VERSION 5.7 ;
  NOWIREEXTENSIONATPIN ON ;
  DIVIDERCHAR "/" ;
  BUSBITCHARS "[]" ;
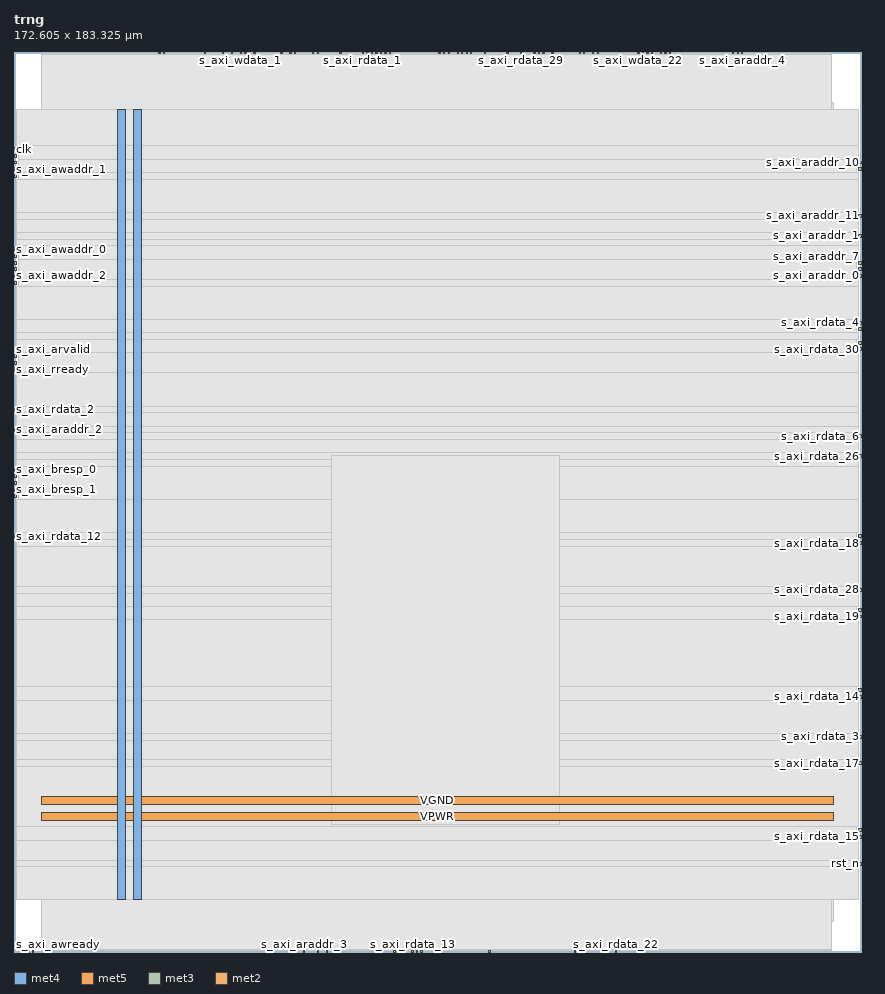
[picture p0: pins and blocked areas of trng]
MACRO trng
  CLASS BLOCK ;
  FOREIGN trng ;
  ORIGIN 0.000 0.000 ;
  SIZE 172.605 BY 183.325 ;
  PIN VGND
    DIRECTION INOUT ;
    USE GROUND ;
    PORT
      LAYER met4 ;
        RECT 24.340 10.640 25.940 171.600 ;
    END
    PORT
      LAYER met5 ;
        RECT 5.520 30.030 166.980 31.630 ;
    END
  END VGND
  PIN VPWR
    DIRECTION INOUT ;
    USE POWER ;
    PORT
      LAYER met4 ;
        RECT 21.040 10.640 22.640 171.600 ;
    END
    PORT
      LAYER met5 ;
        RECT 5.520 26.730 166.980 28.330 ;
    END
  END VPWR
  PIN clk
    DIRECTION INPUT ;
    USE SIGNAL ;
    ANTENNAGATEAREA 1.286700 ;
    ANTENNADIFFAREA 0.434700 ;
    PORT
      LAYER met3 ;
        RECT 0.000 163.240 0.600 163.840 ;
    END
  END clk
  PIN irq
    DIRECTION OUTPUT ;
    USE SIGNAL ;
    ANTENNAGATEAREA 0.434700 ;
    ANTENNADIFFAREA 1.137600 ;
    PORT
      LAYER met2 ;
        RECT 73.690 183.045 73.970 183.325 ;
    END
  END irq
  PIN rst_n
    DIRECTION INPUT ;
    USE SIGNAL ;
    ANTENNAGATEAREA 0.647700 ;
    ANTENNADIFFAREA 0.434700 ;
    PORT
      LAYER met3 ;
        RECT 172.005 17.720 172.605 18.320 ;
    END
  END rst_n
  PIN s_axi_araddr_0
    DIRECTION INPUT ;
    USE SIGNAL ;
    ANTENNAGATEAREA 0.647700 ;
    ANTENNADIFFAREA 0.434700 ;
    PORT
      LAYER met3 ;
        RECT 172.005 137.400 172.605 138.000 ;
    END
  END s_axi_araddr_0
  PIN s_axi_araddr_1
    DIRECTION INPUT ;
    USE SIGNAL ;
    ANTENNAGATEAREA 0.647700 ;
    ANTENNADIFFAREA 0.434700 ;
    PORT
      LAYER met3 ;
        RECT 172.005 145.560 172.605 146.160 ;
    END
  END s_axi_araddr_1
  PIN s_axi_araddr_10
    DIRECTION INPUT ;
    USE SIGNAL ;
    ANTENNAGATEAREA 0.647700 ;
    ANTENNADIFFAREA 0.434700 ;
    PORT
      LAYER met3 ;
        RECT 172.005 160.520 172.605 161.120 ;
    END
  END s_axi_araddr_10
  PIN s_axi_araddr_11
    DIRECTION INPUT ;
    USE SIGNAL ;
    ANTENNAGATEAREA 0.647700 ;
    ANTENNADIFFAREA 0.434700 ;
    PORT
      LAYER met3 ;
        RECT 172.005 149.640 172.605 150.240 ;
    END
  END s_axi_araddr_11
  PIN s_axi_araddr_2
    DIRECTION INPUT ;
    USE SIGNAL ;
    ANTENNAGATEAREA 0.647700 ;
    ANTENNADIFFAREA 0.434700 ;
    PORT
      LAYER met3 ;
        RECT 0.000 106.120 0.600 106.720 ;
    END
  END s_axi_araddr_2
  PIN s_axi_araddr_3
    DIRECTION INPUT ;
    USE SIGNAL ;
    ANTENNAGATEAREA 0.647700 ;
    ANTENNADIFFAREA 0.434700 ;
    PORT
      LAYER met2 ;
        RECT 58.970 0.000 59.250 0.280 ;
    END
  END s_axi_araddr_3
  PIN s_axi_araddr_4
    DIRECTION INPUT ;
    USE SIGNAL ;
    ANTENNAGATEAREA 0.647700 ;
    ANTENNADIFFAREA 0.434700 ;
    PORT
      LAYER met2 ;
        RECT 148.210 183.045 148.490 183.325 ;
    END
  END s_axi_araddr_4
  PIN s_axi_araddr_5
    DIRECTION INPUT ;
    USE SIGNAL ;
    ANTENNAGATEAREA 0.647700 ;
    ANTENNADIFFAREA 0.434700 ;
    PORT
      LAYER met3 ;
        RECT 172.005 138.760 172.605 139.360 ;
    END
  END s_axi_araddr_5
  PIN s_axi_araddr_6
    DIRECTION INPUT ;
    USE SIGNAL ;
    ANTENNAGATEAREA 0.647700 ;
    ANTENNADIFFAREA 0.434700 ;
    PORT
      LAYER met2 ;
        RECT 147.290 183.045 147.570 183.325 ;
    END
  END s_axi_araddr_6
  PIN s_axi_araddr_7
    DIRECTION INPUT ;
    USE SIGNAL ;
    ANTENNAGATEAREA 0.647700 ;
    ANTENNADIFFAREA 0.434700 ;
    PORT
      LAYER met3 ;
        RECT 172.005 140.120 172.605 140.720 ;
    END
  END s_axi_araddr_7
  PIN s_axi_araddr_8
    DIRECTION INPUT ;
    USE SIGNAL ;
    ANTENNAGATEAREA 0.647700 ;
    ANTENNADIFFAREA 0.434700 ;
    PORT
      LAYER met2 ;
        RECT 146.370 183.045 146.650 183.325 ;
    END
  END s_axi_araddr_8
  PIN s_axi_araddr_9
    DIRECTION INPUT ;
    USE SIGNAL ;
    ANTENNAGATEAREA 0.647700 ;
    ANTENNADIFFAREA 0.434700 ;
    PORT
      LAYER met3 ;
        RECT 172.005 159.160 172.605 159.760 ;
    END
  END s_axi_araddr_9
  PIN s_axi_arready
    DIRECTION OUTPUT ;
    USE SIGNAL ;
    PORT
      LAYER met2 ;
        RECT 1.930 0.000 2.210 0.280 ;
    END
  END s_axi_arready
  PIN s_axi_arvalid
    DIRECTION INPUT ;
    USE SIGNAL ;
    ANTENNAGATEAREA 0.647700 ;
    ANTENNADIFFAREA 0.434700 ;
    PORT
      LAYER met3 ;
        RECT 0.000 121.080 0.600 121.680 ;
    END
  END s_axi_arvalid
  PIN s_axi_awaddr_0
    DIRECTION INPUT ;
    USE SIGNAL ;
    ANTENNAGATEAREA 0.647700 ;
    ANTENNADIFFAREA 0.434700 ;
    PORT
      LAYER met3 ;
        RECT 0.000 142.840 0.600 143.440 ;
    END
  END s_axi_awaddr_0
  PIN s_axi_awaddr_1
    DIRECTION INPUT ;
    USE SIGNAL ;
    ANTENNAGATEAREA 0.647700 ;
    ANTENNADIFFAREA 0.434700 ;
    PORT
      LAYER met3 ;
        RECT 0.000 159.160 0.600 159.760 ;
    END
  END s_axi_awaddr_1
  PIN s_axi_awaddr_10
    DIRECTION INPUT ;
    USE SIGNAL ;
    ANTENNAGATEAREA 0.647700 ;
    ANTENNADIFFAREA 0.434700 ;
    PORT
      LAYER met2 ;
        RECT 29.530 183.045 29.810 183.325 ;
    END
  END s_axi_awaddr_10
  PIN s_axi_awaddr_11
    DIRECTION INPUT ;
    USE SIGNAL ;
    ANTENNAGATEAREA 0.647700 ;
    ANTENNADIFFAREA 0.434700 ;
    PORT
      LAYER met3 ;
        RECT 0.000 160.520 0.600 161.120 ;
    END
  END s_axi_awaddr_11
  PIN s_axi_awaddr_2
    DIRECTION INPUT ;
    USE SIGNAL ;
    ANTENNAGATEAREA 0.647700 ;
    ANTENNADIFFAREA 0.434700 ;
    PORT
      LAYER met3 ;
        RECT 0.000 137.400 0.600 138.000 ;
    END
  END s_axi_awaddr_2
  PIN s_axi_awaddr_3
    DIRECTION INPUT ;
    USE SIGNAL ;
    ANTENNAGATEAREA 0.647700 ;
    ANTENNADIFFAREA 0.434700 ;
    PORT
      LAYER met3 ;
        RECT 0.000 138.760 0.600 139.360 ;
    END
  END s_axi_awaddr_3
  PIN s_axi_awaddr_4
    DIRECTION INPUT ;
    USE SIGNAL ;
    ANTENNAGATEAREA 0.647700 ;
    ANTENNADIFFAREA 0.434700 ;
    PORT
      LAYER met3 ;
        RECT 0.000 140.120 0.600 140.720 ;
    END
  END s_axi_awaddr_4
  PIN s_axi_awaddr_5
    DIRECTION INPUT ;
    USE SIGNAL ;
    ANTENNAGATEAREA 0.647700 ;
    ANTENNADIFFAREA 0.434700 ;
    PORT
      LAYER met3 ;
        RECT 0.000 136.040 0.600 136.640 ;
    END
  END s_axi_awaddr_5
  PIN s_axi_awaddr_6
    DIRECTION INPUT ;
    USE SIGNAL ;
    ANTENNAGATEAREA 0.647700 ;
    ANTENNADIFFAREA 0.434700 ;
    PORT
      LAYER met3 ;
        RECT 0.000 157.800 0.600 158.400 ;
    END
  END s_axi_awaddr_6
  PIN s_axi_awaddr_7
    DIRECTION INPUT ;
    USE SIGNAL ;
    ANTENNAGATEAREA 0.647700 ;
    ANTENNADIFFAREA 0.434700 ;
    PORT
      LAYER met3 ;
        RECT 0.000 161.880 0.600 162.480 ;
    END
  END s_axi_awaddr_7
  PIN s_axi_awaddr_8
    DIRECTION INPUT ;
    USE SIGNAL ;
    ANTENNAGATEAREA 0.647700 ;
    ANTENNADIFFAREA 0.434700 ;
    PORT
      LAYER met2 ;
        RECT 30.450 183.045 30.730 183.325 ;
    END
  END s_axi_awaddr_8
  PIN s_axi_awaddr_9
    DIRECTION INPUT ;
    USE SIGNAL ;
    ANTENNAGATEAREA 0.647700 ;
    ANTENNADIFFAREA 0.434700 ;
    PORT
      LAYER met3 ;
        RECT 0.000 141.480 0.600 142.080 ;
    END
  END s_axi_awaddr_9
  PIN s_axi_awready
    DIRECTION OUTPUT ;
    USE SIGNAL ;
    PORT
      LAYER met2 ;
        RECT 2.850 0.000 3.130 0.280 ;
    END
  END s_axi_awready
  PIN s_axi_awvalid
    DIRECTION INPUT ;
    USE SIGNAL ;
    ANTENNAGATEAREA 0.647700 ;
    ANTENNADIFFAREA 0.434700 ;
    PORT
      LAYER met2 ;
        RECT 38.730 183.045 39.010 183.325 ;
    END
  END s_axi_awvalid
  PIN s_axi_bready
    DIRECTION INPUT ;
    USE SIGNAL ;
    ANTENNAGATEAREA 0.647700 ;
    ANTENNADIFFAREA 0.434700 ;
    PORT
      LAYER met2 ;
        RECT 42.410 183.045 42.690 183.325 ;
    END
  END s_axi_bready
  PIN s_axi_bresp_0
    DIRECTION OUTPUT ;
    USE SIGNAL ;
    ANTENNAGATEAREA 0.434700 ;
    ANTENNADIFFAREA 0.434700 ;
    PORT
      LAYER met3 ;
        RECT 0.000 97.960 0.600 98.560 ;
    END
  END s_axi_bresp_0
  PIN s_axi_bresp_1
    DIRECTION OUTPUT ;
    USE SIGNAL ;
    ANTENNAGATEAREA 0.434700 ;
    ANTENNADIFFAREA 0.775300 ;
    PORT
      LAYER met3 ;
        RECT 0.000 95.240 0.600 95.840 ;
    END
  END s_axi_bresp_1
  PIN s_axi_bvalid
    DIRECTION OUTPUT ;
    USE SIGNAL ;
    ANTENNAGATEAREA 0.434700 ;
    ANTENNADIFFAREA 1.137600 ;
    PORT
      LAYER met2 ;
        RECT 48.850 183.045 49.130 183.325 ;
    END
  END s_axi_bvalid
  PIN s_axi_rdata_0
    DIRECTION OUTPUT ;
    USE SIGNAL ;
    ANTENNAGATEAREA 0.434700 ;
    ANTENNADIFFAREA 1.137600 ;
    PORT
      LAYER met3 ;
        RECT 0.000 92.520 0.600 93.120 ;
    END
  END s_axi_rdata_0
  PIN s_axi_rdata_1
    DIRECTION OUTPUT ;
    USE SIGNAL ;
    ANTENNAGATEAREA 0.434700 ;
    ANTENNADIFFAREA 1.137600 ;
    PORT
      LAYER met2 ;
        RECT 70.930 183.045 71.210 183.325 ;
    END
  END s_axi_rdata_1
  PIN s_axi_rdata_10
    DIRECTION OUTPUT ;
    USE SIGNAL ;
    ANTENNAGATEAREA 0.434700 ;
    ANTENNADIFFAREA 1.137600 ;
    PORT
      LAYER met2 ;
        RECT 63.570 0.000 63.850 0.280 ;
    END
  END s_axi_rdata_10
  PIN s_axi_rdata_11
    DIRECTION OUTPUT ;
    USE SIGNAL ;
    ANTENNAGATEAREA 0.434700 ;
    ANTENNADIFFAREA 1.137600 ;
    PORT
      LAYER met2 ;
        RECT 61.730 0.000 62.010 0.280 ;
    END
  END s_axi_rdata_11
  PIN s_axi_rdata_12
    DIRECTION OUTPUT ;
    USE SIGNAL ;
    ANTENNAGATEAREA 0.434700 ;
    ANTENNADIFFAREA 1.137600 ;
    PORT
      LAYER met3 ;
        RECT 0.000 84.360 0.600 84.960 ;
    END
  END s_axi_rdata_12
  PIN s_axi_rdata_13
    DIRECTION OUTPUT ;
    USE SIGNAL ;
    ANTENNAGATEAREA 0.434700 ;
    ANTENNADIFFAREA 1.137600 ;
    PORT
      LAYER met2 ;
        RECT 81.050 0.000 81.330 0.280 ;
    END
  END s_axi_rdata_13
  PIN s_axi_rdata_14
    DIRECTION OUTPUT ;
    USE SIGNAL ;
    ANTENNAGATEAREA 0.434700 ;
    ANTENNADIFFAREA 1.137600 ;
    PORT
      LAYER met3 ;
        RECT 172.005 51.720 172.605 52.320 ;
    END
  END s_axi_rdata_14
  PIN s_axi_rdata_15
    DIRECTION OUTPUT ;
    USE SIGNAL ;
    ANTENNAGATEAREA 0.434700 ;
    ANTENNADIFFAREA 1.137600 ;
    PORT
      LAYER met3 ;
        RECT 172.005 23.160 172.605 23.760 ;
    END
  END s_axi_rdata_15
  PIN s_axi_rdata_16
    DIRECTION OUTPUT ;
    USE SIGNAL ;
    ANTENNAGATEAREA 0.434700 ;
    ANTENNADIFFAREA 1.137600 ;
    PORT
      LAYER met3 ;
        RECT 172.005 24.520 172.605 25.120 ;
    END
  END s_axi_rdata_16
  PIN s_axi_rdata_17
    DIRECTION OUTPUT ;
    USE SIGNAL ;
    ANTENNAGATEAREA 0.434700 ;
    ANTENNADIFFAREA 1.137600 ;
    PORT
      LAYER met3 ;
        RECT 172.005 38.120 172.605 38.720 ;
    END
  END s_axi_rdata_17
  PIN s_axi_rdata_18
    DIRECTION OUTPUT ;
    USE SIGNAL ;
    ANTENNAGATEAREA 0.434700 ;
    ANTENNADIFFAREA 1.137600 ;
    PORT
      LAYER met3 ;
        RECT 172.005 83.000 172.605 83.600 ;
    END
  END s_axi_rdata_18
  PIN s_axi_rdata_19
    DIRECTION OUTPUT ;
    USE SIGNAL ;
    ANTENNAGATEAREA 0.434700 ;
    ANTENNADIFFAREA 1.137600 ;
    PORT
      LAYER met3 ;
        RECT 172.005 68.040 172.605 68.640 ;
    END
  END s_axi_rdata_19
  PIN s_axi_rdata_2
    DIRECTION OUTPUT ;
    USE SIGNAL ;
    ANTENNAGATEAREA 0.434700 ;
    ANTENNADIFFAREA 1.137600 ;
    PORT
      LAYER met3 ;
        RECT 0.000 110.200 0.600 110.800 ;
    END
  END s_axi_rdata_2
  PIN s_axi_rdata_20
    DIRECTION OUTPUT ;
    USE SIGNAL ;
    ANTENNAGATEAREA 0.434700 ;
    ANTENNADIFFAREA 1.137600 ;
    PORT
      LAYER met2 ;
        RECT 96.690 0.000 96.970 0.280 ;
    END
  END s_axi_rdata_20
  PIN s_axi_rdata_21
    DIRECTION OUTPUT ;
    USE SIGNAL ;
    ANTENNAGATEAREA 0.434700 ;
    ANTENNADIFFAREA 1.137600 ;
    PORT
      LAYER met2 ;
        RECT 77.370 0.000 77.650 0.280 ;
    END
  END s_axi_rdata_21
  PIN s_axi_rdata_22
    DIRECTION OUTPUT ;
    USE SIGNAL ;
    ANTENNAGATEAREA 0.434700 ;
    ANTENNADIFFAREA 1.137600 ;
    PORT
      LAYER met2 ;
        RECT 122.450 0.000 122.730 0.280 ;
    END
  END s_axi_rdata_22
  PIN s_axi_rdata_23
    DIRECTION OUTPUT ;
    USE SIGNAL ;
    ANTENNAGATEAREA 0.434700 ;
    ANTENNADIFFAREA 1.137600 ;
    PORT
      LAYER met2 ;
        RECT 114.170 0.000 114.450 0.280 ;
    END
  END s_axi_rdata_23
  PIN s_axi_rdata_24
    DIRECTION OUTPUT ;
    USE SIGNAL ;
    ANTENNAGATEAREA 0.434700 ;
    ANTENNADIFFAREA 1.137600 ;
    PORT
      LAYER met3 ;
        RECT 172.005 69.400 172.605 70.000 ;
    END
  END s_axi_rdata_24
  PIN s_axi_rdata_25
    DIRECTION OUTPUT ;
    USE SIGNAL ;
    ANTENNAGATEAREA 0.434700 ;
    ANTENNADIFFAREA 1.137600 ;
    PORT
      LAYER met3 ;
        RECT 172.005 84.360 172.605 84.960 ;
    END
  END s_axi_rdata_25
  PIN s_axi_rdata_26
    DIRECTION OUTPUT ;
    USE SIGNAL ;
    ANTENNAGATEAREA 0.434700 ;
    ANTENNADIFFAREA 1.137600 ;
    PORT
      LAYER met3 ;
        RECT 172.005 100.680 172.605 101.280 ;
    END
  END s_axi_rdata_26
  PIN s_axi_rdata_27
    DIRECTION OUTPUT ;
    USE SIGNAL ;
    ANTENNAGATEAREA 0.434700 ;
    ANTENNADIFFAREA 1.137600 ;
    PORT
      LAYER met3 ;
        RECT 172.005 126.520 172.605 127.120 ;
    END
  END s_axi_rdata_27
  PIN s_axi_rdata_28
    DIRECTION OUTPUT ;
    USE SIGNAL ;
    ANTENNAGATEAREA 0.434700 ;
    ANTENNADIFFAREA 1.137600 ;
    PORT
      LAYER met3 ;
        RECT 172.005 73.480 172.605 74.080 ;
    END
  END s_axi_rdata_28
  PIN s_axi_rdata_29
    DIRECTION OUTPUT ;
    USE SIGNAL ;
    ANTENNAGATEAREA 0.434700 ;
    ANTENNADIFFAREA 1.137600 ;
    PORT
      LAYER met2 ;
        RECT 103.130 183.045 103.410 183.325 ;
    END
  END s_axi_rdata_29
  PIN s_axi_rdata_3
    DIRECTION OUTPUT ;
    USE SIGNAL ;
    ANTENNAGATEAREA 0.434700 ;
    ANTENNADIFFAREA 1.137600 ;
    PORT
      LAYER met3 ;
        RECT 172.005 43.560 172.605 44.160 ;
    END
  END s_axi_rdata_3
  PIN s_axi_rdata_30
    DIRECTION OUTPUT ;
    USE SIGNAL ;
    ANTENNAGATEAREA 0.434700 ;
    ANTENNADIFFAREA 1.137600 ;
    PORT
      LAYER met3 ;
        RECT 172.005 122.440 172.605 123.040 ;
    END
  END s_axi_rdata_30
  PIN s_axi_rdata_31
    DIRECTION OUTPUT ;
    USE SIGNAL ;
    ANTENNAGATEAREA 0.434700 ;
    ANTENNADIFFAREA 1.137600 ;
    PORT
      LAYER met2 ;
        RECT 86.570 183.045 86.850 183.325 ;
    END
  END s_axi_rdata_31
  PIN s_axi_rdata_4
    DIRECTION OUTPUT ;
    USE SIGNAL ;
    ANTENNAGATEAREA 0.434700 ;
    ANTENNADIFFAREA 1.137600 ;
    PORT
      LAYER met3 ;
        RECT 172.005 127.880 172.605 128.480 ;
    END
  END s_axi_rdata_4
  PIN s_axi_rdata_5
    DIRECTION OUTPUT ;
    USE SIGNAL ;
    ANTENNAGATEAREA 0.434700 ;
    ANTENNADIFFAREA 1.137600 ;
    PORT
      LAYER met3 ;
        RECT 172.005 123.800 172.605 124.400 ;
    END
  END s_axi_rdata_5
  PIN s_axi_rdata_6
    DIRECTION OUTPUT ;
    USE SIGNAL ;
    ANTENNAGATEAREA 0.434700 ;
    ANTENNADIFFAREA 1.137600 ;
    PORT
      LAYER met3 ;
        RECT 172.005 104.760 172.605 105.360 ;
    END
  END s_axi_rdata_6
  PIN s_axi_rdata_7
    DIRECTION OUTPUT ;
    USE SIGNAL ;
    ANTENNAGATEAREA 0.434700 ;
    ANTENNADIFFAREA 1.137600 ;
    PORT
      LAYER met3 ;
        RECT 172.005 53.080 172.605 53.680 ;
    END
  END s_axi_rdata_7
  PIN s_axi_rdata_8
    DIRECTION OUTPUT ;
    USE SIGNAL ;
    ANTENNAGATEAREA 0.434700 ;
    ANTENNADIFFAREA 1.137600 ;
    PORT
      LAYER met2 ;
        RECT 81.970 0.000 82.250 0.280 ;
    END
  END s_axi_rdata_8
  PIN s_axi_rdata_9
    DIRECTION OUTPUT ;
    USE SIGNAL ;
    ANTENNAGATEAREA 0.434700 ;
    ANTENNADIFFAREA 1.137600 ;
    PORT
      LAYER met2 ;
        RECT 82.890 0.000 83.170 0.280 ;
    END
  END s_axi_rdata_9
  PIN s_axi_rready
    DIRECTION INPUT ;
    USE SIGNAL ;
    ANTENNAGATEAREA 0.647700 ;
    ANTENNADIFFAREA 0.434700 ;
    PORT
      LAYER met3 ;
        RECT 0.000 118.360 0.600 118.960 ;
    END
  END s_axi_rready
  PIN s_axi_rresp_0
    DIRECTION OUTPUT ;
    USE SIGNAL ;
    ANTENNAGATEAREA 0.434700 ;
    ANTENNADIFFAREA 0.775300 ;
    PORT
      LAYER met3 ;
        RECT 0.000 96.600 0.600 97.200 ;
    END
  END s_axi_rresp_0
  PIN s_axi_rresp_1
    DIRECTION OUTPUT ;
    USE SIGNAL ;
    ANTENNAGATEAREA 0.434700 ;
    ANTENNADIFFAREA 0.775300 ;
    PORT
      LAYER met3 ;
        RECT 0.000 93.880 0.600 94.480 ;
    END
  END s_axi_rresp_1
  PIN s_axi_rvalid
    DIRECTION OUTPUT ;
    USE SIGNAL ;
    ANTENNAGATEAREA 0.434700 ;
    ANTENNADIFFAREA 1.137600 ;
    PORT
      LAYER met3 ;
        RECT 0.000 119.720 0.600 120.320 ;
    END
  END s_axi_rvalid
  PIN s_axi_wdata_0
    DIRECTION INPUT ;
    USE SIGNAL ;
    ANTENNAGATEAREA 0.647700 ;
    ANTENNADIFFAREA 0.434700 ;
    PORT
      LAYER met2 ;
        RECT 56.210 183.045 56.490 183.325 ;
    END
  END s_axi_wdata_0
  PIN s_axi_wdata_1
    DIRECTION INPUT ;
    USE SIGNAL ;
    ANTENNAGATEAREA 0.647700 ;
    ANTENNADIFFAREA 0.434700 ;
    PORT
      LAYER met2 ;
        RECT 46.090 183.045 46.370 183.325 ;
    END
  END s_axi_wdata_1
  PIN s_axi_wdata_10
    DIRECTION INPUT ;
    USE SIGNAL ;
    ANTENNAGATEAREA 0.647700 ;
    ANTENNADIFFAREA 0.434700 ;
    PORT
      LAYER met2 ;
        RECT 116.010 183.045 116.290 183.325 ;
    END
  END s_axi_wdata_10
  PIN s_axi_wdata_11
    DIRECTION INPUT ;
    USE SIGNAL ;
    ANTENNAGATEAREA 0.647700 ;
    ANTENNADIFFAREA 0.434700 ;
    PORT
      LAYER met2 ;
        RECT 76.450 183.045 76.730 183.325 ;
    END
  END s_axi_wdata_11
  PIN s_axi_wdata_12
    DIRECTION INPUT ;
    USE SIGNAL ;
    ANTENNAGATEAREA 0.647700 ;
    ANTENNADIFFAREA 0.434700 ;
    PORT
      LAYER met2 ;
        RECT 115.090 183.045 115.370 183.325 ;
    END
  END s_axi_wdata_12
  PIN s_axi_wdata_13
    DIRECTION INPUT ;
    USE SIGNAL ;
    ANTENNAGATEAREA 0.647700 ;
    ANTENNADIFFAREA 0.434700 ;
    PORT
      LAYER met2 ;
        RECT 66.330 183.045 66.610 183.325 ;
    END
  END s_axi_wdata_13
  PIN s_axi_wdata_14
    DIRECTION INPUT ;
    USE SIGNAL ;
    ANTENNAGATEAREA 0.647700 ;
    ANTENNADIFFAREA 0.434700 ;
    PORT
      LAYER met2 ;
        RECT 118.770 183.045 119.050 183.325 ;
    END
  END s_axi_wdata_14
  PIN s_axi_wdata_15
    DIRECTION INPUT ;
    USE SIGNAL ;
    ANTENNAGATEAREA 0.647700 ;
    ANTENNADIFFAREA 0.434700 ;
    PORT
      LAYER met2 ;
        RECT 71.850 183.045 72.130 183.325 ;
    END
  END s_axi_wdata_15
  PIN s_axi_wdata_16
    DIRECTION INPUT ;
    USE SIGNAL ;
    ANTENNAGATEAREA 0.647700 ;
    ANTENNADIFFAREA 0.434700 ;
    PORT
      LAYER met2 ;
        RECT 61.730 183.045 62.010 183.325 ;
    END
  END s_axi_wdata_16
  PIN s_axi_wdata_17
    DIRECTION INPUT ;
    USE SIGNAL ;
    ANTENNAGATEAREA 0.647700 ;
    ANTENNADIFFAREA 0.434700 ;
    PORT
      LAYER met2 ;
        RECT 75.530 183.045 75.810 183.325 ;
    END
  END s_axi_wdata_17
  PIN s_axi_wdata_18
    DIRECTION INPUT ;
    USE SIGNAL ;
    ANTENNAGATEAREA 0.647700 ;
    ANTENNADIFFAREA 0.434700 ;
    PORT
      LAYER met2 ;
        RECT 54.370 183.045 54.650 183.325 ;
    END
  END s_axi_wdata_18
  PIN s_axi_wdata_19
    DIRECTION INPUT ;
    USE SIGNAL ;
    ANTENNAGATEAREA 0.647700 ;
    ANTENNADIFFAREA 0.434700 ;
    PORT
      LAYER met2 ;
        RECT 95.770 183.045 96.050 183.325 ;
    END
  END s_axi_wdata_19
  PIN s_axi_wdata_2
    DIRECTION INPUT ;
    USE SIGNAL ;
    ANTENNAGATEAREA 0.647700 ;
    ANTENNADIFFAREA 0.434700 ;
    PORT
      LAYER met2 ;
        RECT 57.130 183.045 57.410 183.325 ;
    END
  END s_axi_wdata_2
  PIN s_axi_wdata_20
    DIRECTION INPUT ;
    USE SIGNAL ;
    ANTENNAGATEAREA 0.647700 ;
    ANTENNADIFFAREA 0.434700 ;
    PORT
      LAYER met2 ;
        RECT 91.170 183.045 91.450 183.325 ;
    END
  END s_axi_wdata_20
  PIN s_axi_wdata_21
    DIRECTION INPUT ;
    USE SIGNAL ;
    ANTENNAGATEAREA 0.647700 ;
    ANTENNADIFFAREA 0.434700 ;
    PORT
      LAYER met2 ;
        RECT 88.410 183.045 88.690 183.325 ;
    END
  END s_axi_wdata_21
  PIN s_axi_wdata_22
    DIRECTION INPUT ;
    USE SIGNAL ;
    ANTENNAGATEAREA 0.647700 ;
    ANTENNADIFFAREA 0.434700 ;
    PORT
      LAYER met2 ;
        RECT 127.050 183.045 127.330 183.325 ;
    END
  END s_axi_wdata_22
  PIN s_axi_wdata_23
    DIRECTION INPUT ;
    USE SIGNAL ;
    ANTENNAGATEAREA 0.647700 ;
    ANTENNADIFFAREA 0.434700 ;
    PORT
      LAYER met2 ;
        RECT 74.610 183.045 74.890 183.325 ;
    END
  END s_axi_wdata_23
  PIN s_axi_wdata_24
    DIRECTION INPUT ;
    USE SIGNAL ;
    ANTENNAGATEAREA 0.647700 ;
    ANTENNADIFFAREA 0.434700 ;
    PORT
      LAYER met2 ;
        RECT 127.970 183.045 128.250 183.325 ;
    END
  END s_axi_wdata_24
  PIN s_axi_wdata_25
    DIRECTION INPUT ;
    USE SIGNAL ;
    ANTENNAGATEAREA 0.647700 ;
    ANTENNADIFFAREA 0.434700 ;
    PORT
      LAYER met2 ;
        RECT 132.570 183.045 132.850 183.325 ;
    END
  END s_axi_wdata_25
  PIN s_axi_wdata_26
    DIRECTION INPUT ;
    USE SIGNAL ;
    ANTENNAGATEAREA 0.647700 ;
    ANTENNADIFFAREA 0.434700 ;
    PORT
      LAYER met2 ;
        RECT 100.370 183.045 100.650 183.325 ;
    END
  END s_axi_wdata_26
  PIN s_axi_wdata_27
    DIRECTION INPUT ;
    USE SIGNAL ;
    ANTENNAGATEAREA 0.647700 ;
    ANTENNADIFFAREA 0.434700 ;
    PORT
      LAYER met2 ;
        RECT 92.090 183.045 92.370 183.325 ;
    END
  END s_axi_wdata_27
  PIN s_axi_wdata_28
    DIRECTION INPUT ;
    USE SIGNAL ;
    ANTENNAGATEAREA 0.647700 ;
    ANTENNADIFFAREA 0.434700 ;
    PORT
      LAYER met2 ;
        RECT 128.890 183.045 129.170 183.325 ;
    END
  END s_axi_wdata_28
  PIN s_axi_wdata_29
    DIRECTION INPUT ;
    USE SIGNAL ;
    ANTENNAGATEAREA 0.647700 ;
    ANTENNADIFFAREA 0.434700 ;
    PORT
      LAYER met2 ;
        RECT 72.770 183.045 73.050 183.325 ;
    END
  END s_axi_wdata_29
  PIN s_axi_wdata_3
    DIRECTION INPUT ;
    USE SIGNAL ;
    ANTENNAGATEAREA 0.647700 ;
    ANTENNADIFFAREA 0.434700 ;
    PORT
      LAYER met2 ;
        RECT 117.850 183.045 118.130 183.325 ;
    END
  END s_axi_wdata_3
  PIN s_axi_wdata_30
    DIRECTION INPUT ;
    USE SIGNAL ;
    ANTENNAGATEAREA 0.647700 ;
    ANTENNADIFFAREA 0.434700 ;
    PORT
      LAYER met2 ;
        RECT 109.570 183.045 109.850 183.325 ;
    END
  END s_axi_wdata_30
  PIN s_axi_wdata_31
    DIRECTION INPUT ;
    USE SIGNAL ;
    ANTENNAGATEAREA 0.647700 ;
    ANTENNADIFFAREA 0.434700 ;
    PORT
      LAYER met2 ;
        RECT 133.490 183.045 133.770 183.325 ;
    END
  END s_axi_wdata_31
  PIN s_axi_wdata_4
    DIRECTION INPUT ;
    USE SIGNAL ;
    ANTENNAGATEAREA 0.647700 ;
    ANTENNADIFFAREA 0.434700 ;
    PORT
      LAYER met2 ;
        RECT 93.010 183.045 93.290 183.325 ;
    END
  END s_axi_wdata_4
  PIN s_axi_wdata_5
    DIRECTION INPUT ;
    USE SIGNAL ;
    ANTENNAGATEAREA 0.647700 ;
    ANTENNADIFFAREA 0.434700 ;
    PORT
      LAYER met2 ;
        RECT 131.650 183.045 131.930 183.325 ;
    END
  END s_axi_wdata_5
  PIN s_axi_wdata_6
    DIRECTION INPUT ;
    USE SIGNAL ;
    ANTENNAGATEAREA 0.647700 ;
    ANTENNADIFFAREA 0.434700 ;
    PORT
      LAYER met2 ;
        RECT 129.810 183.045 130.090 183.325 ;
    END
  END s_axi_wdata_6
  PIN s_axi_wdata_7
    DIRECTION INPUT ;
    USE SIGNAL ;
    ANTENNAGATEAREA 0.647700 ;
    ANTENNADIFFAREA 0.434700 ;
    PORT
      LAYER met2 ;
        RECT 105.890 183.045 106.170 183.325 ;
    END
  END s_axi_wdata_7
  PIN s_axi_wdata_8
    DIRECTION INPUT ;
    USE SIGNAL ;
    ANTENNAGATEAREA 0.647700 ;
    ANTENNADIFFAREA 0.434700 ;
    PORT
      LAYER met2 ;
        RECT 106.810 183.045 107.090 183.325 ;
    END
  END s_axi_wdata_8
  PIN s_axi_wdata_9
    DIRECTION INPUT ;
    USE SIGNAL ;
    ANTENNAGATEAREA 0.647700 ;
    ANTENNADIFFAREA 0.434700 ;
    PORT
      LAYER met2 ;
        RECT 60.810 183.045 61.090 183.325 ;
    END
  END s_axi_wdata_9
  PIN s_axi_wready
    DIRECTION OUTPUT ;
    USE SIGNAL ;
    PORT
      LAYER met2 ;
        RECT 3.770 0.000 4.050 0.280 ;
    END
  END s_axi_wready
  PIN s_axi_wstrb_0
    DIRECTION INPUT ;
    USE SIGNAL ;
    ANTENNAGATEAREA 0.647700 ;
    ANTENNADIFFAREA 0.434700 ;
    PORT
      LAYER met2 ;
        RECT 44.250 183.045 44.530 183.325 ;
    END
  END s_axi_wstrb_0
  PIN s_axi_wstrb_1
    DIRECTION INPUT ;
    USE SIGNAL ;
    ANTENNAGATEAREA 0.647700 ;
    ANTENNADIFFAREA 0.434700 ;
    PORT
      LAYER met2 ;
        RECT 107.730 183.045 108.010 183.325 ;
    END
  END s_axi_wstrb_1
  PIN s_axi_wstrb_2
    DIRECTION INPUT ;
    USE SIGNAL ;
    ANTENNAGATEAREA 0.647700 ;
    ANTENNADIFFAREA 0.434700 ;
    PORT
      LAYER met2 ;
        RECT 87.490 183.045 87.770 183.325 ;
    END
  END s_axi_wstrb_2
  PIN s_axi_wstrb_3
    DIRECTION INPUT ;
    USE SIGNAL ;
    ANTENNAGATEAREA 0.647700 ;
    ANTENNADIFFAREA 0.434700 ;
    PORT
      LAYER met2 ;
        RECT 90.250 183.045 90.530 183.325 ;
    END
  END s_axi_wstrb_3
  PIN s_axi_wvalid
    DIRECTION INPUT ;
    USE SIGNAL ;
    ANTENNAGATEAREA 0.647700 ;
    ANTENNADIFFAREA 0.434700 ;
    PORT
      LAYER met2 ;
        RECT 47.010 183.045 47.290 183.325 ;
    END
  END s_axi_wvalid
  OBS
      LAYER nwell ;
        RECT 5.330 10.795 167.170 171.550 ;
      LAYER li1 ;
        RECT 5.520 10.795 166.980 171.445 ;
      LAYER met1 ;
        RECT 5.520 6.160 166.980 173.020 ;
      LAYER met2 ;
        RECT 5.610 182.765 29.250 183.045 ;
        RECT 30.090 182.765 30.170 183.045 ;
        RECT 31.010 182.765 38.450 183.045 ;
        RECT 39.290 182.765 42.130 183.045 ;
        RECT 42.970 182.765 43.970 183.045 ;
        RECT 44.810 182.765 45.810 183.045 ;
        RECT 46.650 182.765 46.730 183.045 ;
        RECT 47.570 182.765 48.570 183.045 ;
        RECT 49.410 182.765 54.090 183.045 ;
        RECT 54.930 182.765 55.930 183.045 ;
        RECT 56.770 182.765 56.850 183.045 ;
        RECT 57.690 182.765 60.530 183.045 ;
        RECT 61.370 182.765 61.450 183.045 ;
        RECT 62.290 182.765 66.050 183.045 ;
        RECT 66.890 182.765 70.650 183.045 ;
        RECT 71.490 182.765 71.570 183.045 ;
        RECT 72.410 182.765 72.490 183.045 ;
        RECT 73.330 182.765 73.410 183.045 ;
        RECT 74.250 182.765 74.330 183.045 ;
        RECT 75.170 182.765 75.250 183.045 ;
        RECT 76.090 182.765 76.170 183.045 ;
        RECT 77.010 182.765 86.290 183.045 ;
        RECT 87.130 182.765 87.210 183.045 ;
        RECT 88.050 182.765 88.130 183.045 ;
        RECT 88.970 182.765 89.970 183.045 ;
        RECT 90.810 182.765 90.890 183.045 ;
        RECT 91.730 182.765 91.810 183.045 ;
        RECT 92.650 182.765 92.730 183.045 ;
        RECT 93.570 182.765 95.490 183.045 ;
        RECT 96.330 182.765 100.090 183.045 ;
        RECT 100.930 182.765 102.850 183.045 ;
        RECT 103.690 182.765 105.610 183.045 ;
        RECT 106.450 182.765 106.530 183.045 ;
        RECT 107.370 182.765 107.450 183.045 ;
        RECT 108.290 182.765 109.290 183.045 ;
        RECT 110.130 182.765 114.810 183.045 ;
        RECT 115.650 182.765 115.730 183.045 ;
        RECT 116.570 182.765 117.570 183.045 ;
        RECT 118.410 182.765 118.490 183.045 ;
        RECT 119.330 182.765 126.770 183.045 ;
        RECT 127.610 182.765 127.690 183.045 ;
        RECT 128.530 182.765 128.610 183.045 ;
        RECT 129.450 182.765 129.530 183.045 ;
        RECT 130.370 182.765 131.370 183.045 ;
        RECT 132.210 182.765 132.290 183.045 ;
        RECT 133.130 182.765 133.210 183.045 ;
        RECT 134.050 182.765 146.090 183.045 ;
        RECT 146.930 182.765 147.010 183.045 ;
        RECT 147.850 182.765 147.930 183.045 ;
        RECT 148.770 182.765 166.430 183.045 ;
        RECT 5.610 0.560 166.430 182.765 ;
        RECT 5.610 0.280 58.690 0.560 ;
        RECT 59.530 0.280 61.450 0.560 ;
        RECT 62.290 0.280 63.290 0.560 ;
        RECT 64.130 0.280 77.090 0.560 ;
        RECT 77.930 0.280 80.770 0.560 ;
        RECT 81.610 0.280 81.690 0.560 ;
        RECT 82.530 0.280 82.610 0.560 ;
        RECT 83.450 0.280 96.410 0.560 ;
        RECT 97.250 0.280 113.890 0.560 ;
        RECT 114.730 0.280 122.170 0.560 ;
        RECT 123.010 0.280 166.430 0.560 ;
      LAYER met3 ;
        RECT 0.600 164.240 172.005 171.525 ;
        RECT 1.000 161.520 172.005 164.240 ;
        RECT 1.000 158.760 171.605 161.520 ;
        RECT 1.000 157.400 172.005 158.760 ;
        RECT 0.600 150.640 172.005 157.400 ;
        RECT 0.600 149.240 171.605 150.640 ;
        RECT 0.600 146.560 172.005 149.240 ;
        RECT 0.600 145.160 171.605 146.560 ;
        RECT 0.600 143.840 172.005 145.160 ;
        RECT 1.000 141.120 172.005 143.840 ;
        RECT 1.000 137.000 171.605 141.120 ;
        RECT 1.000 135.640 172.005 137.000 ;
        RECT 0.600 128.880 172.005 135.640 ;
        RECT 0.600 126.120 171.605 128.880 ;
        RECT 0.600 124.800 172.005 126.120 ;
        RECT 0.600 122.080 171.605 124.800 ;
        RECT 1.000 122.040 171.605 122.080 ;
        RECT 1.000 117.960 172.005 122.040 ;
        RECT 0.600 111.200 172.005 117.960 ;
        RECT 1.000 109.800 172.005 111.200 ;
        RECT 0.600 107.120 172.005 109.800 ;
        RECT 1.000 105.760 172.005 107.120 ;
        RECT 1.000 105.720 171.605 105.760 ;
        RECT 0.600 104.360 171.605 105.720 ;
        RECT 0.600 101.680 172.005 104.360 ;
        RECT 0.600 100.280 171.605 101.680 ;
        RECT 0.600 98.960 172.005 100.280 ;
        RECT 1.000 92.120 172.005 98.960 ;
        RECT 0.600 85.360 172.005 92.120 ;
        RECT 1.000 83.960 171.605 85.360 ;
        RECT 0.600 82.600 171.605 83.960 ;
        RECT 0.600 74.480 172.005 82.600 ;
        RECT 0.600 73.080 171.605 74.480 ;
        RECT 0.600 70.400 172.005 73.080 ;
        RECT 0.600 67.640 171.605 70.400 ;
        RECT 0.600 54.080 172.005 67.640 ;
        RECT 0.600 51.320 171.605 54.080 ;
        RECT 0.600 44.560 172.005 51.320 ;
        RECT 0.600 43.160 171.605 44.560 ;
        RECT 0.600 39.120 172.005 43.160 ;
        RECT 0.600 37.720 171.605 39.120 ;
        RECT 0.600 25.520 172.005 37.720 ;
        RECT 0.600 22.760 171.605 25.520 ;
        RECT 0.600 18.720 172.005 22.760 ;
        RECT 0.600 17.320 171.605 18.720 ;
        RECT 0.600 10.715 172.005 17.320 ;
      LAYER met4 ;
        RECT 64.695 26.015 111.025 101.145 ;
  END
END trng
END LIBRARY

